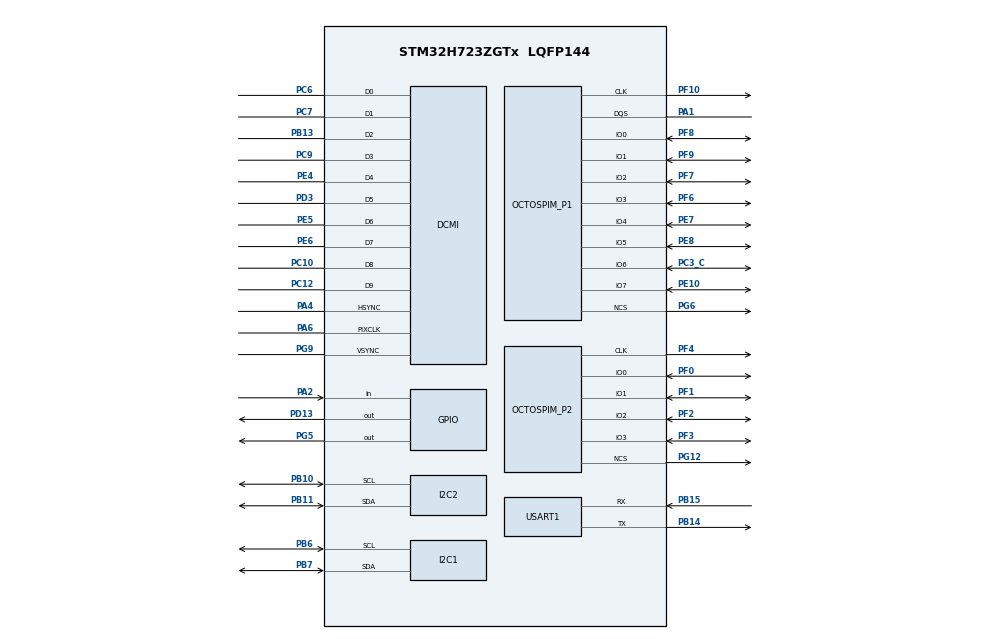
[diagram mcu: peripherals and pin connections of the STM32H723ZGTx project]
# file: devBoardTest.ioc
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CORTEX_M7.CPU_DCache=Enabled
CORTEX_M7.CPU_ICache=Enabled
I2C1.Timing=0x108088C8
I2C2.Timing=0x108088C8
Mcu.Family=STM32H7
Mcu.Name=STM32H723ZGTx
Mcu.Package=LQFP144
NVIC.OCTOSPI2_IRQn=true\:0\:0\:false\:false\:true\:true\:true\:true
NVIC.PriorityGroup=NVIC_PRIORITYGROUP_4
OCTOSPI1.ChipSelectBoundary=0
OCTOSPI1.ChipSelectHighTime=1
OCTOSPI1.ClockMode=HAL_OSPI_CLOCK_MODE_0
OCTOSPI1.ClockPrescaler=4
OCTOSPI1.DelayBlockBypass=HAL_OSPI_DELAY_BLOCK_USED
OCTOSPI1.DelayHoldQuarterCycle=HAL_OSPI_DHQC_ENABLE
OCTOSPI1.DeviceSize=27
OCTOSPI1.MaxTran=0
OCTOSPI1.MemoryType=HAL_OSPI_MEMTYPE_APMEMORY
OCTOSPI1.Refresh=0
OCTOSPI1.SampleShifting=HAL_OSPI_SAMPLE_SHIFTING_NONE
OCTOSPI1.WrapSize=HAL_OSPI_WRAP_NOT_SUPPORTED
OCTOSPI2.ClockPrescaler=8
OCTOSPI2.DelayBlockBypass=HAL_OSPI_DELAY_BLOCK_USED
OCTOSPI2.DeviceSize=30
PA1.Mode=OCTOSPI1_Port1_DQS
PA1.Signal=OCTOSPIM_P1_DQS
PA2.GPIO_PuPd=GPIO_PULLUP
PA2.Signal=GPIO_Input
PA4.Mode=Slave_10_bits_External_Synchro
PA4.Signal=DCMI_HSYNC
PA6.Mode=Slave_10_bits_External_Synchro
PA6.Signal=DCMI_PIXCLK
PB10.Mode=I2C
PB10.Signal=I2C2_SCL
PB11.Mode=I2C
PB11.Signal=I2C2_SDA
PB13.Mode=Slave_10_bits_External_Synchro
PB13.Signal=DCMI_D2
PB14.Mode=Asynchronous
PB14.Signal=USART1_TX
PB15.Mode=Asynchronous
PB15.Signal=USART1_RX
PB6.Mode=I2C
PB6.Signal=I2C1_SCL
PB7.Mode=I2C
PB7.Signal=I2C1_SDA
PC10.Mode=Slave_10_bits_External_Synchro
PC10.Signal=DCMI_D8
PC12.Mode=Slave_10_bits_External_Synchro
PC12.Signal=DCMI_D9
PC3_C.Mode=OCTOSPI1_IOH_Port1H
PC3_C.Signal=OCTOSPIM_P1_IO6
PC6.Mode=Slave_10_bits_External_Synchro
PC6.Signal=DCMI_D0
PC7.Mode=Slave_10_bits_External_Synchro
PC7.Signal=DCMI_D1
PC9.Mode=Slave_10_bits_External_Synchro
PC9.Signal=DCMI_D3
PD13.GPIO_ModeDefaultOutputPP=GPIO_MODE_OUTPUT_PP
PD13.GPIO_PuPd=GPIO_PULLUP
PD13.PinState=GPIO_PIN_SET
PD13.Signal=GPIO_Output
PD3.Mode=Slave_10_bits_External_Synchro
PD3.Signal=DCMI_D5
PE10.Mode=OCTOSPI1_IOH_Port1H
PE10.Signal=OCTOSPIM_P1_IO7
PE4.Mode=Slave_10_bits_External_Synchro
PE4.Signal=DCMI_D4
PE5.Mode=Slave_10_bits_External_Synchro
PE5.Signal=DCMI_D6
PE6.Mode=Slave_10_bits_External_Synchro
PE6.Signal=DCMI_D7
PE7.Mode=OCTOSPI1_IOH_Port1H
PE7.Signal=OCTOSPIM_P1_IO4
PE8.Mode=OCTOSPI1_IOH_Port1H
PE8.Signal=OCTOSPIM_P1_IO5
PF0.Mode=OCTOSPI2_IOL_Port2L
PF0.Signal=OCTOSPIM_P2_IO0
PF1.Mode=OCTOSPI2_IOL_Port2L
PF1.Signal=OCTOSPIM_P2_IO1
PF10.Mode=O1_P1_CLK
PF10.Signal=OCTOSPIM_P1_CLK
PF2.Mode=OCTOSPI2_IOL_Port2L
PF2.Signal=OCTOSPIM_P2_IO2
PF3.Mode=OCTOSPI2_IOL_Port2L
PF3.Signal=OCTOSPIM_P2_IO3
PF4.Mode=O2_P2_CLK
PF4.Signal=OCTOSPIM_P2_CLK
PF6.Mode=OCTOSPI1_IOL_Port1L
PF6.Signal=OCTOSPIM_P1_IO3
PF7.Mode=OCTOSPI1_IOL_Port1L
PF7.Signal=OCTOSPIM_P1_IO2
PF8.Mode=OCTOSPI1_IOL_Port1L
PF8.Signal=OCTOSPIM_P1_IO0
PF9.Mode=OCTOSPI1_IOL_Port1L
PF9.Signal=OCTOSPIM_P1_IO1
PG12.Mode=OCTOSPI2_Port2_NCS
PG12.Signal=OCTOSPIM_P2_NCS
PG5.GPIO_PuPd=GPIO_PULLUP
PG5.Signal=GPIO_Output
PG6.GPIO_PuPd=GPIO_PULLUP
PG6.Mode=OCTOSPI1_Port1_NCS
PG6.Signal=OCTOSPIM_P1_NCS
PG9.Mode=Slave_10_bits_External_Synchro
PG9.Signal=DCMI_VSYNC
ProjectManager.HeapSize=0x200
ProjectManager.StackSize=0x400
ProjectManager.TargetToolchain=STM32CubeIDE
RCC.ADCFreq_Value=96000000
RCC.APB1Freq_Value=68750000
RCC.APB2Freq_Value=68750000
RCC.APB3Freq_Value=137500000
RCC.APB4Freq_Value=137500000
RCC.CortexFreq_Value=275000000
RCC.D1PPRE=RCC_APB3_DIV2
RCC.D2PPRE1=RCC_APB1_DIV4
RCC.D2PPRE2=RCC_APB2_DIV4
RCC.D3PPRE=RCC_APB4_DIV2
RCC.DIVM1=4
RCC.DIVM2=4
RCC.DIVN1=17
RCC.DIVN2=12
RCC.DIVP1=1
RCC.DIVQ2=1
RCC.HCLKFreq_Value=275000000
RCC.HSE_VALUE=50000000
RCC.QSPICLockSelection=RCC_OSPICLKSOURCE_CLKP
RCC.SYSCLKFreq_VALUE=275000000
RCC.SYSCLKSource=RCC_SYSCLKSOURCE_PLLCLK
RCC.USBFreq_Value=137500000
USART1.VirtualMode-Asynchronous=VM_ASYNC
VP_OCTOSPI1_VS_octo.Mode=octo_mode
VP_OCTOSPI2_VS_quad.Mode=quad_mode
board=custom

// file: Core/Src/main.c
/* USER CODE BEGIN Header */
/**
  ******************************************************************************
  * @file           : main.c
  * @brief          : Main program body
  ******************************************************************************
  * @attention
  *
  * Copyright (c) 2023 STMicroelectronics.
  * All rights reserved.
  *
  * This software is licensed under terms that can be found in the LICENSE file
  * in the root directory of this software component.
  * If no LICENSE file comes with this software, it is provided AS-IS.
  *
  ******************************************************************************
  */
/* USER CODE END Header */
#include "main.h"
#include "dcmi.h"
#include "i2c.h"
#include "octospi.h"
#include "usart.h"
#include "gpio.h"

/* USER CODE BEGIN Includes */
#include "log.h"
#include "string.h"
#include "stdbool.h"
#include "INA236.h"
#include "PCA9543.h"
#include "TMP117.h"
#include "aps6408.h"
#include "aps6408_conf.h"
#include "W25Nxx.h"
#include "ICM20948.h"
/* USER CODE END Includes */

/* USER CODE BEGIN PV */
uint8_t aTxBuffer[] = " **OCTOSPI/Octal-spi PSRAM Memory-mapped communication example** **OCTOSPI/Octal-spi PSRAM Memory-mapped communication example** **OCTOSPI/Octal-spi PSRAM Memory-mapped communication example** **OCTOSPI/Octal-spi PSRAM Memory-mapped communication example**";
uint8_t aRxBuffer[512];
/* USER CODE END PV */

void SystemClock_Config(void);
void PeriphCommonClock_Config(void);
/* USER CODE BEGIN PFP */
void Configure_APMemory(void);
static void test_NAND(void);
static void test_PSRAM(void);
/* USER CODE END PFP */

/* USER CODE BEGIN 0 */
INA236_dev INA33Bus;
INA236_dev INA18Bus;
TMP117_dev temp_A;
PCA9543_dev i2c_switch;
W25Nxx_dev W25N;
ICM20948_dev ICM;
/* USER CODE END 0 */

int main(void)
{

  /* Enable I-Cache---------------------------------------------------------*/
  SCB_EnableICache();

  /* Enable D-Cache---------------------------------------------------------*/
  SCB_EnableDCache();

  /* MCU Configuration--------------------------------------------------------*/

  /* Reset of all peripherals, Initializes the Flash interface and the Systick. */
  HAL_Init();

  /* Configure the system clock */
  SystemClock_Config();

/* Configure the peripherals common clocks */
  PeriphCommonClock_Config();

  /* USER CODE BEGIN SysInit */
  HAL_GPIO_WritePin(GPIOG, GPIO_PIN_5, GPIO_PIN_RESET); //Memory reset
  HAL_GPIO_WritePin(GPIOG, GPIO_PIN_6, GPIO_PIN_SET);
  /* USER CODE END SysInit */

  /* Initialize all configured peripherals */
  MX_GPIO_Init();
  MX_USART1_UART_Init();
  MX_DCMI_Init();
  MX_I2C1_Init();
  MX_I2C2_Init();
  MX_OCTOSPI1_Init();
  MX_OCTOSPI2_Init();
  /* USER CODE BEGIN 2 */

  log_info("Main Init");

  //test_PSRAM();
  test_NAND();

  /* USER CODE END 2 */

  /* Infinite loop */
  /* USER CODE BEGIN WHILE */
  INA236_setup(&INA33Bus, &i2c_bus_2, INA236_ADDR_1);
  INA236_setup(&INA18Bus, &i2c_bus_2, INA236_ADDR_1);
  PCA9543_setup(&i2c_switch, &i2c_bus_2, PCA9543_ADDR_1);
  TMP117_setup(&temp_A, &i2c_bus_2, TMP117_ADDR_1);
  ICM20948_setup(&ICM, &i2c_bus_1, ICM20948_ADDR_1);

  if (PCA9543_set_channel(&i2c_switch, PCA9543_CHANNEL_1) != HAL_OK)
  {
	  log_error("Unable to set i2c switch channel");
  }

  /*
  if (HAL_I2C_IsDeviceReady(&hi2c2, PCA9543_ADDR_1, 2, 1000) != HAL_OK)
  {
	  log_error("Unable to communicate with i2c switch");
  } */

  if (HAL_I2C_IsDeviceReady(&hi2c2, TMP117_ADDR_1 << 1, 2, 1000) != HAL_OK)
  {
	  log_error("Unable to communicate with TMP117_A");
  }
  else {
	  log_info("TMP117_A Ready");
  }
/*
  if (HAL_I2C_IsDeviceReady(&hi2c1, INA236_ADDR_1, 2, 1000) != HAL_OK)
  {
	  log_error("Unable to communicate with INA236");
  }
  else {
	  log_info("INA236 Ready");
  }
*/
  if (HAL_I2C_IsDeviceReady(&hi2c1, ICM20948_ADDR_1 << 1, 2, 1000) != HAL_OK)
  {
	  log_error("Unable to communicate with ICM-20948");
  }
  else {
	  log_info("ICM-20948 Ready");
  }

  ICM20948_set_accel_sens(&ICM, 1);
  //ICM20948_set_gyro_sens(&ICM, 1);
  //mainly using for testing but will be part of setup in future

  while (1)
  {

    /* USER CODE END WHILE */

    /* USER CODE BEGIN 3 */
	float temperature_A = 0;
	if (TMP117_read_temperature(&temp_A, &temperature_A) == HAL_OK) {
		log_info("Temperature A:%f", temperature_A);
	}
	else {
		log_error("Unable to get temp A");
	}

	/*
	float voltage = 0;
	if (INA236_get_bus_voltage(&INA18Bus, &voltage) == HAL_OK) {
	  log_info("1.8v Bus Voltage:%f", voltage);
	}
	else {
	  log_error("Error getting 1.8v bus voltage");
	}
	*/

	ICM20948_switch_bank(&ICM, 2);
	uint8_t accel_sens;
	if (ICM20948_get_accel_sens(&ICM, &accel_sens) == HAL_OK) {
		log_info("Accel Sens:%hu", accel_sens);
	}
	else {
		log_error("Unable to get Accel Sens");
	}
	ICM20948_switch_bank(&ICM, 0);
	float accelx = 0;
	if (ICM20948_get_x_accel(&ICM, &accelx, &accel_sens) == HAL_OK) {
		log_info("X Acceleration:%hu", accelx);
	}
	else {
		log_error("Unable to get X Accel");
	}

	float accely = 0;
	if (ICM20948_get_y_accel(&ICM, &accely, &accel_sens) == HAL_OK) {
		log_info("Y Acceleration:%hu", accely);
	}
	else {
		log_error("Unable to get Y Accel");
	}

	float accelz = 0;
	if (ICM20948_get_z_accel(&ICM, &accelz, &accel_sens) == HAL_OK) {
		log_info("Z Acceleration:%hu", accelz);
	}
	else {
		log_error("Unable to get Z Accel");
	}
	ICM20948_switch_bank(&ICM, 2);
	uint8_t gyro_sens = 0;
	if (ICM20948_get_gyro_sens(&ICM, &gyro_sens) == HAL_OK) {
		log_info("Gyro Sens:%hu", gyro_sens);
	}
	else {
		log_error("Unable to get Gyro Sens");
	}
	ICM20948_switch_bank(&ICM, 0);
	float gyrox = 0;
	if (ICM20948_get_x_gyro(&ICM, &gyrox, &gyro_sens) == HAL_OK) {
		log_info("X Gyro:%hu", gyrox);
	}
	else {
		log_error("Unable to get X Gyro");
	}

	float gyroy = 0;
	if (ICM20948_get_y_gyro(&ICM, &gyroy, &gyro_sens) == HAL_OK) {
		log_info("Y Gyro:%hu", gyroy);
	}
	else {
		log_error("Unable to get Y Gyro");
	}

	float gyroz = 0;
	if (ICM20948_get_z_gyro(&ICM, &gyroz, &gyro_sens) == HAL_OK) {
		log_info("Z Gyro:%hu", gyroz);
	}
	else {
		log_error("Unable to get Z Gyro");
	}

	HAL_Delay(1000);

  }
  /* USER CODE END 3 */
}

void SystemClock_Config(void)
{
  RCC_OscInitTypeDef RCC_OscInitStruct = {0};
  RCC_ClkInitTypeDef RCC_ClkInitStruct = {0};
  HAL_PWREx_ConfigSupply(PWR_LDO_SUPPLY);
__HAL_PWR_VOLTAGESCALING_CONFIG(PWR_REGULATOR_VOLTAGE_SCALE2);

  while(!__HAL_PWR_GET_FLAG(PWR_FLAG_VOSRDY)) {}

  __HAL_RCC_PLL_PLLSOURCE_CONFIG(RCC_PLLSOURCE_HSI);

  RCC_OscInitStruct.OscillatorType = RCC_OSCILLATORTYPE_HSI;
  RCC_OscInitStruct.HSIState = RCC_HSI_DIV1;
  RCC_OscInitStruct.HSICalibrationValue = RCC_HSICALIBRATION_DEFAULT;
  RCC_OscInitStruct.PLL.PLLState = RCC_PLL_ON;
  RCC_OscInitStruct.PLL.PLLSource = RCC_PLLSOURCE_HSI;
  RCC_OscInitStruct.PLL.PLLM = 4;
  RCC_OscInitStruct.PLL.PLLN = 16;
  RCC_OscInitStruct.PLL.PLLP = 1;
  RCC_OscInitStruct.PLL.PLLQ = 2;
  RCC_OscInitStruct.PLL.PLLR = 2;
  RCC_OscInitStruct.PLL.PLLRGE = RCC_PLL1VCIRANGE_3;
  RCC_OscInitStruct.PLL.PLLVCOSEL = RCC_PLL1VCOWIDE;
  RCC_OscInitStruct.PLL.PLLFRACN = 0;
  if (HAL_RCC_OscConfig(&RCC_OscInitStruct) != HAL_OK)
  {
    Error_Handler();
  }

  /** Initializes the CPU, AHB and APB buses clocks
  */
  RCC_ClkInitStruct.ClockType = RCC_CLOCKTYPE_HCLK|RCC_CLOCKTYPE_SYSCLK
                              |RCC_CLOCKTYPE_PCLK1|RCC_CLOCKTYPE_PCLK2
                              |RCC_CLOCKTYPE_D3PCLK1|RCC_CLOCKTYPE_D1PCLK1;
  RCC_ClkInitStruct.SYSCLKSource = RCC_SYSCLKSOURCE_PLLCLK;
  RCC_ClkInitStruct.SYSCLKDivider = RCC_SYSCLK_DIV1;
  RCC_ClkInitStruct.AHBCLKDivider = RCC_HCLK_DIV2;
  RCC_ClkInitStruct.APB3CLKDivider = RCC_APB3_DIV2;
  RCC_ClkInitStruct.APB1CLKDivider = RCC_APB1_DIV2;
  RCC_ClkInitStruct.APB2CLKDivider = RCC_APB2_DIV2;
  RCC_ClkInitStruct.APB4CLKDivider = RCC_APB4_DIV2;

  if (HAL_RCC_ClockConfig(&RCC_ClkInitStruct, FLASH_LATENCY_2) != HAL_OK)
  {
    Error_Handler();
  }
}

void PeriphCommonClock_Config(void)
{
  RCC_PeriphCLKInitTypeDef PeriphClkInitStruct = {0};

  /** Initializes the peripherals clock
  */
  PeriphClkInitStruct.PeriphClockSelection = RCC_PERIPHCLK_CKPER;
  PeriphClkInitStruct.CkperClockSelection = RCC_CLKPSOURCE_HSI;
  if (HAL_RCCEx_PeriphCLKConfig(&PeriphClkInitStruct) != HAL_OK)
  {
    Error_Handler();
  }
}

/* USER CODE BEGIN 4 */

static void test_NAND(void)
{
	W25N_setup(&W25N, &hospi2, 0);

	uint32_t nand_id = 0;
	uint8_t statReg = 0;
	if (W25N_ReadJEDECID(&W25N, &nand_id) == W25N_OK) {
	  log_info("W25N ID: %X", nand_id);
	}
	else {
	  log_error("Unable to read from W25N");
	}
	W25N_Write_Enable(&W25N);

	W25N_Read_Status_Reg(&W25N, W25N_STATUS_REG, &statReg);
	log_info("W25N status: %X", statReg);
	W25N_Read_Status_Reg(&W25N, W25N_CONFIG_REG, &statReg);
	log_info("W25N config: %X", statReg);
	W25N_Read_Status_Reg(&W25N, W25N_PROTECTION_REG, &statReg);
	log_info("W25N protection: %X", statReg);
	W25N_Write_Status_Reg(&W25N, W25N_PROTECTION_REG, 0x00); //Disable memory protection
	W25N_Write_Status_Reg(&W25N, W25N_CONFIG_REG, 0x18); //Enable ECC and buffer

	W25N_Block_Erase(&W25N, 0x0026);
	W25N_Read_Status_Reg(&W25N, W25N_STATUS_REG, &statReg);
	log_info("W25N status: %X", statReg);
	W25N_Read_Status_Reg(&W25N, W25N_PROTECTION_REG, &statReg);
	log_info("W25N protection: %X", statReg);
	W25N_Wait_Until_Not_Busy(&W25N, 30000);

	memset(aRxBuffer, 0xff, 512);

	W25N_Write_Enable(&W25N); //Must be called before Data load

	if (W25N_Load_Data_Quad(&W25N, 0x00, aTxBuffer, 256) != W25N_OK) {
	  log_error("W25N Unable to load data");
	}

	W25N_Program_Execute(&W25N, 0x0026);
	W25N_Read_Status_Reg(&W25N, W25N_STATUS_REG, &statReg);
	log_info("W25N status after execute: %X", statReg);
	W25N_Wait_Until_Not_Busy(&W25N, 30000);

	W25N_Read_Status_Reg(&W25N, W25N_STATUS_REG, &statReg);
	log_info("W25N status after execute done: %X", statReg);
	W25N_Page_Data_Read(&W25N, 0x0026);
	W25N_Read_Status_Reg(&W25N, W25N_STATUS_REG, &statReg);
	log_info("W25N status after page load: %X", statReg);
	W25N_Wait_Until_Not_Busy(&W25N, 30000);

	W25N_Read_Status_Reg(&W25N, W25N_STATUS_REG, &statReg);
	log_info("W25N status after page load done: %X", statReg);
	if (W25N_Read_Output_Quad(&W25N, 0x00, aRxBuffer, 256) != W25N_OK) {
	  log_error("W25N unable to read output");
	}

	if (aRxBuffer[0] == aTxBuffer[0]) {
	  log_info("----W25N R/W Success----");
	}
	else {
	  log_error("W25N R/W Failure");
	}
}

static void test_PSRAM(void)
{
	__HAL_OSPI_DISABLE(&hospi1);
	HAL_Delay(100);
	CLEAR_BIT(hospi1.Instance->DCR1, OCTOSPI_DCR1_FRCK);
	__HAL_OSPI_ENABLE(&hospi1);
	HAL_GPIO_WritePin(GPIOG, GPIO_PIN_5, GPIO_PIN_SET); //Memory reset pin HIGH
	HAL_GPIO_WritePin(GPIOG, GPIO_PIN_6, GPIO_PIN_RESET);

	if (APS6408_Write(&hospi1, aTxBuffer, 0x00, 4, DUMMY_CLOCK_CYCLES_WRITE, APS6408_MR8_BL_32_BYTES) != HAL_OK) {
	  log_error("Unable to write to APS6408");
	}
	uint32_t testData = 0;
	if (APS6408_Read(&hospi1, (uint8_t *)&testData, 0x00, 4, DUMMY_CLOCK_CYCLES_READ, APS6408_MR8_BL_32_BYTES) != HAL_OK) {
	  log_error("Unable to write to APS6408");
	}

	if (testData != *((uint32_t *)aTxBuffer)) {
	  log_error("APS6048 Read/Write Fail");
	}
	else {
	  log_info("APS6048 Read/Write Success");
	}

	if (APS6408_EnableMemoryMappedMode(&hospi1, APS6408_READ_LATENCY_5, DUMMY_CLOCK_CYCLES_WRITE, APS6408_MR8_BL_32_BYTES) != HAL_OK)
	{
	  log_error("Unable to start APS6408 memory mapped mode");
	}

	__IO uint8_t *mem_addr;
	uint32_t address = 0;
	uint16_t index1;/*index1 counter of bytes used when reading/writing 256 bytes buffer */
	uint16_t index2;/*index2 counter of 256 bytes buffer used */
	bool noErrors = true;
	mem_addr = (__IO uint8_t *)(OCTOSPI1_BASE + address);
	//Writing 1Mbyte (256Byte BUFFERSIZE x 4096 times)
	for (index2 = 0; index2 < EXTENDEDBUFFERSIZE/BUFFERSIZE; index2++)
	{
		for (index1 = 0; index1 < BUFFERSIZE; index1++)
		{
			*mem_addr = aTxBuffer[index1];
			mem_addr++;
		}
	}
	//----------------------------------------------------------------------
	//Reading Sequence of 1Mbyte
	mem_addr = (__IO uint8_t *)(OCTOSPI1_BASE + address);
	//Reading 1Mbyte (256Byte BUFFERSIZE x 4096 times)
	for (index2 = 0; index2 < EXTENDEDBUFFERSIZE/BUFFERSIZE; index2++) {
		for (index1 = 0; index1 < BUFFERSIZE; index1++)
		{
			uint8_t data = *mem_addr;
			if (data != aTxBuffer[index1])
			{
				//if data read is corrupted we can toggle a led here: example blue led
				//log_error("Data Corrupt, %d != %d", data, aTxBuffer[index1]);
				noErrors = false;
			}
				mem_addr++;
		}
	}

	if (noErrors) {
		log_info("PSRAM data transfer success");
	}
	else {
		log_info("PSRAM data transfer failure");
	}
}

void Configure_APMemory(void)
{
  /* MR0 register for read and write */
  uint8_t regW_MR0[2]={0x24,0x0D}; /* To configure AP memory Latency Type and drive Strength */
  uint8_t regR_MR0[2]={0};

  /* MR8 register for read and write */
  uint8_t regW_MR8[2]={0x0B,0x08}; /* To configure AP memory Burst Type */
  uint8_t regR_MR8[2]={0};

  /*Read Latency */
  uint8_t latency=6;

  /* Configure Read Latency and drive Strength */
  if (APS6408_WriteReg(&hospi1, APS6408_MR0_ADDRESS, regW_MR0[0]) != HAL_OK)
  {
    Error_Handler();
  }

  /* Check MR0 configuration */
  if (APS6408_ReadReg(&hospi1, APS6408_MR0_ADDRESS, regR_MR0, latency ) != HAL_OK)
  {
    Error_Handler();
  }

    /* Check MR0 configuration */
  if (regR_MR0 [0] != regW_MR0 [0])
  {
	  log_error("MR0 Set failed");
  }

  /* Configure Burst Length */
  if (APS6408_WriteReg(&hospi1, APS6408_MR8_ADDRESS, regW_MR8[0]) != HAL_OK)
  {
    Error_Handler();
  }

  /* Check MR8 configuration */
  if (APS6408_ReadReg(&hospi1, APS6408_MR8_ADDRESS, regR_MR8, 6) != HAL_OK)
  {
    Error_Handler();
  }

  if (regR_MR8[0] != regW_MR8[0])
  {
	  log_error("MR8 Set Failed");
  }
}
/* USER CODE END 4 */

void Error_Handler(void)
{
  /* USER CODE BEGIN Error_Handler_Debug */
  /* User can add his own implementation to report the HAL error return state */
	log_error("Unrecoverable Error");
  __disable_irq();
  while (1)
  {
  }
  /* USER CODE END Error_Handler_Debug */
}
